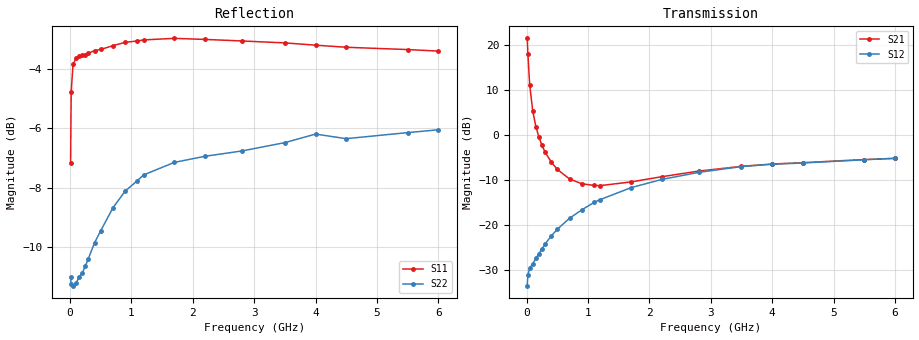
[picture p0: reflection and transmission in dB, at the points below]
! Infineon Technologies  Discrete & RF Semiconductors
! BFS17W
! Si NPN RF Bipolar Junction Transistor in SOT323
! VCE = 0.5 V  IC = 25 mA
! Common Emitter S-Parameters:  August  1999
# GHz  S  MA  R  50
!  f  S11  S21  S12  S22
! GHz  MAG  ANG  MAG  ANG  MAG  ANG  MAG  ANG
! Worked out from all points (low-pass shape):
!   36 points, 10 MHz to 6 GHz, reference 50 ohm
!   highest |S21| = 21.47 dB at 10 MHz (marker M1); lowest = -11.2 dB at 1.2 GHz (marker M2)
!   |S21| within 3 dB of the highest: start of sweep to 18.81 MHz
!   lowest |S11| = -7.2 dB at 10 MHz (marker M3), VSWR 2.56, Z = 26.2 - j26.1 ohm
!   |S11| at or under -10 dB: nowhere
!   |S22| runs from -11.3 to -6.1 dB; largest |S21 - S12| = 12
!   S11 on the Smith chart (normalised r, x): 10 MHz: 0.52, -0.52; 50 MHz: 0.22, -0.13; 500 MHz: 0.19, +0.08; 1.7 GHz: 0.19, +0.36; 3.5 GHz: 0.28, +0.75; 6 GHz: 0.50, +1.19
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0.01  0.438 -113.4  11.84 139.9  0.0213 49.8  0.2815 -77.9
0.02  0.5767 -141.3  7.999 119.6  0.0281 34.8  0.2739 -116.1
0.05  0.6417 -164.1  3.586 99.8  0.0334 26.8  0.2725 -150.5
0.1  0.6569 -173.8  1.842 88.8  0.0373 32.4  0.2749 -163.5
0.15  0.6621 -177.3  1.245 82.5  0.0428 39.1  0.2821 -166.7
0.2  0.6657 -179.9  0.949 77.3  0.0484 44.5  0.286 -168.0
0.25  0.6659 177.9  0.769 72.9  0.0543 48.7  0.294 -169.1
0.3  0.6699 176.4  0.649 69.0  0.0618 52.0  0.3026 -169.4
0.4  0.6766 173.2  0.503 62.3  0.0757 56.6  0.3217 -170.9
0.5  0.6798 170.3  0.416 57.2  0.0902 59.1  0.3369 -172.2
0.7  0.6896 165.0  0.325 51.1  0.1195 61.4  0.3684 -176.6
0.9  0.6987 159.6  0.288 49.0  0.1482 61.8  0.393 179.1
1.1  0.7024 154.1  0.276 48.8  0.1788 60.4  0.4093 174.9
1.2  0.7053 151.7  0.275 48.3  0.1924 59.7  0.4183 172.6
1.7  0.7095 139.4  0.302 47.2  0.2608 54.7  0.4391 163.6
2.2  0.7066 128.2  0.345 44.3  0.3216 49.0  0.4496 156.5
2.8  0.7024 115.9  0.398 38.5  0.3853 41.7  0.4589 148.2
3.5  0.6972 103.2  0.45 31.1  0.4469 33.0  0.474 139.7
4  0.6911 95.7  0.477 26.1  0.4752 26.9  0.4899 133.2
4.5  0.6855 88.7  0.494 21.7  0.4899 22.2  0.4813 126.8
5.5  0.6794 78.4  0.535 13.6  0.5321 14.3  0.4927 117.8
6  0.6754 74.2  0.55 9.8  0.5536 10.4  0.4981 112.6
